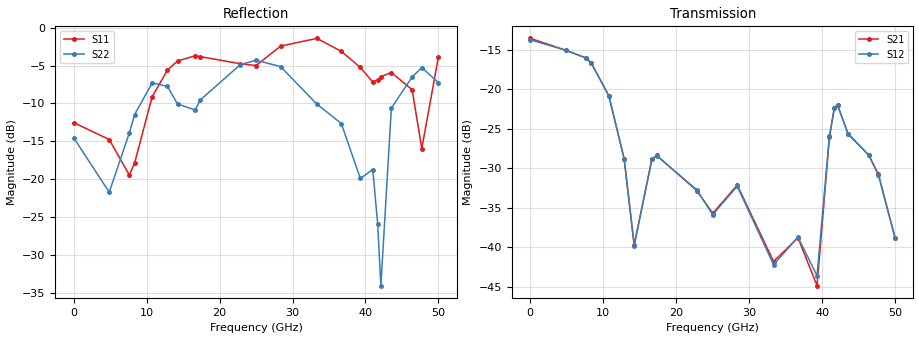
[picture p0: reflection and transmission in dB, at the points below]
!Keysight Technologies,N5245B,MY58422270,A.16.20.02
!Date: Thursday, March 05, 2026 01:00:31
!Correction: S11(C  2-Port  )
!S21(C  2-Port  )
!S12(C  2-Port  )
!S22(C  2-Port  )
!S2P File: Measurements: S11, S21, S12, S22:
# Hz S  dB  R 50
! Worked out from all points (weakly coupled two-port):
!   3201 points, 10 MHz to 50 GHz, reference 50 ohm
!   highest |S21| = -13.59 dB at 10 MHz (marker M1); lowest = -44.9 dB at 39.3 GHz (marker M2)
!   lowest |S11| = -19.5 dB at 7.633 GHz (marker M3), VSWR 1.24, Z = 40.4 - j1.14 ohm
!   |S11| at or under -10 dB: start of sweep to 10.39 GHz; 46.73 GHz to 48.26 GHz (1.528 GHz wide, 3.22 % of centre)
!   |S22| runs from -34.3 to -4.0 dB; largest |S21 - S12| = 0.0068
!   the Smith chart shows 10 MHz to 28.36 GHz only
!   S11 on the Smith chart (normalised r, x): 10 MHz: 1.62, -0.02; 10.77 GHz: 0.52, +0.25; 14.24 GHz: 1.70, +1.84; 17.33 GHz: 0.75, -1.44; 22.82 GHz: 0.27, -0.13; 28.36 GHz: 0.19, +0.61
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1e7  -12.53 -1.4  -13.59 3.9  -13.77 2.5  -14.53 37.2
4.884025e9  -14.77 -149.0  -15.10 155.1  -15.10 155.0  -21.73 -160.2
7.633475e9  -19.46 -172.5  -16.07 30.1  -16.07 30.3  -13.91 178.2
8.352081e9  -17.89 -163.8  -16.70 -4.0  -16.69 -3.9  -11.48 160.4
1.077347e10  -9.10 143.7  -20.87 -114.5  -20.86 -114.4  -7.28 88.7
1.28668e10  -5.58 83.5  -28.84 160.4  -28.85 160.3  -7.75 7.3
1.424153e10  -4.39 34.9  -39.70 174.6  -39.83 175.1  -10.08 -78.6
1.667854e10  -3.70 -42.0  -28.85 146.0  -28.84 145.4  -10.86 161.8
1.733466e10  -3.81 -60.5  -28.41 119.3  -28.44 119.6  -9.56 145.2
2.281794e10  -4.75 -164.4  -32.86 -37.3  -32.76 -37.4  -4.89 62.6
2.5005e10  -4.99 174.5  -35.74 -77.5  -35.90 -77.9  -4.29 45.8
2.83637e10  -2.43 116.0  -32.16 -149.4  -32.30 -150.2  -5.13 8.8
3.334708e10  -1.40 35.6  -41.83 59.7  -42.23 62.5  -10.09 3.0
3.669016e10  -3.12 -31.3  -38.81 26.5  -38.74 25.8  -12.65 -23.0
3.929902e10  -5.24 -34.7  -44.89 129.3  -43.64 129.9  -19.91 -26.1
4.10018e10  -7.19 -53.4  -26.10 19.1  -25.92 17.5  -18.73 -11.1
4.167354e10  -6.86 -55.0  -22.35 -41.5  -22.42 -41.2  -25.92 -30.8
4.211095e10  -6.45 -55.8  -21.99 -84.8  -22.06 -85.6  -34.08 54.6
4.354817e10  -5.92 -72.9  -25.70 -164.6  -25.63 -165.3  -10.61 80.5
4.639135e10  -8.18 -143.8  -28.35 41.9  -28.39 42.1  -6.50 51.0
4.771921e10  -15.96 69.2  -30.81 -11.6  -30.90 -11.1  -5.27 34.5
5e10  -3.85 -72.3  -38.88 -132.2  -38.85 -140.7  -7.24 4.3
